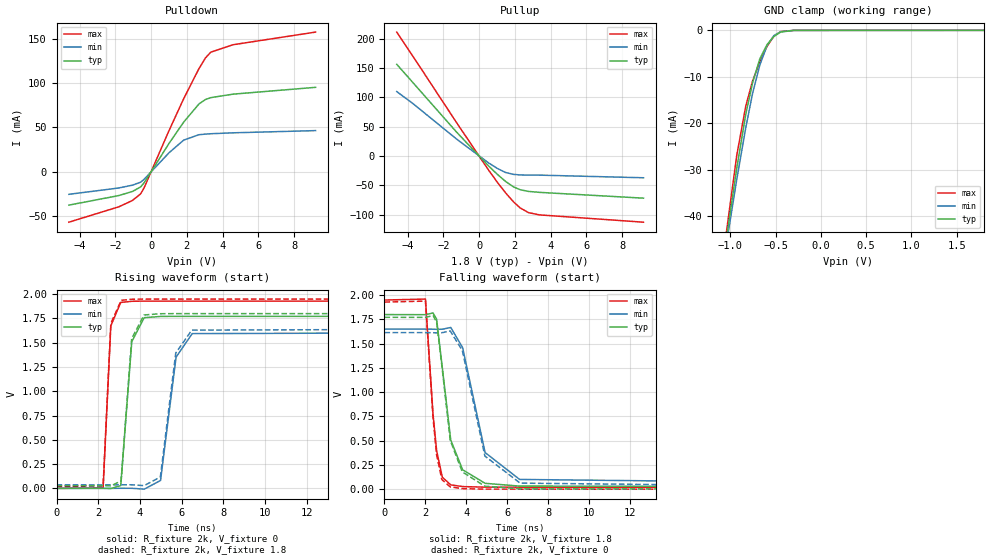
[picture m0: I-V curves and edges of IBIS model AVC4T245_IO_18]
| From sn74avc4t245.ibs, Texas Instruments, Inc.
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[Model]   AVC4T245_IO_18
Model_type  I/O
Vinl=0.5775
Vinh=1.2675
Enable   Active-Low
Vref =   0
Rref =   2000
Cref =   15p
Vmeas =   0.9
| variable   typ   min   max
C_comp   5.14pF   4.46pF   5.82pF
| C_pullup   4.67pF   3.49pF   6.82pF
| C_pulldown   4.57pF   4.04pF   4.94pF
| C_tri-state   5.14pF   4.46pF   5.82pF
[Temperature Range]   40   100   -40
| Ambient temperature   25   85   -40
[Voltage range]   1.8   1.65   1.95
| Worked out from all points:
|   slope of the pulldown table from 0 to 0.27 V, typ, clamps not added: 30.8 ohm
|   slope of the pullup table from 0 to 0.27 V, typ, clamps not added: 31.4 ohm
|   GND clamp passes 1 mA (typ) near -0.50 V on its own axis
|   rising waveform, R_fixture 2k, V_fixture 0: 20-80 % time 305ps typ, 478ps min, 201ps max; typ from 0 V to 1.77 V
|   falling waveform, R_fixture 2k, V_fixture 1.8: 20-80 % time 644ps typ, 986ps min, 377ps max; typ from 1.8 V to 0.027 V
|   rising waveform, R_fixture 2k, V_fixture 1.8: 20-80 % time 303ps typ, 469ps min, 199ps max; typ from 0.027 V to 1.8 V
|   falling waveform, R_fixture 2k, V_fixture 0: 20-80 % time 646ps typ, 986ps min, 364ps max; typ from 1.77 V to 0 V
[GND Clamp]
| AVC4T245_IO_18
|   Voltage   I(typ)   I(min)   I(max)
-4.6V     -600.6mA   -549.4mA   -665.2mA
-1.1V     -52.36mA   -52.84mA   -51.77mA
-1.075V   -48.9mA    -49.7mA    -47.87mA
-930mV    -29.64mA   -32.08mA   -26.89mA
-830mV    -18.03mA   -20.88mA   -16.26mA
-755mV    -11.28mA   -13.55mA   -10.89mA
-675mV    -6.13mA    -7.456mA   -6.788mA
-595mV    -3.055mA   -3.264mA   -3.436mA
-520mV    -1.318mA   -1.135mA   -1.268mA
-445mV    -373.4uA   -312.3uA   -266.4uA
-300mV    -9.535uA   -12.1uA    -2.471uA
1.8V      917.3pA    144.8nA    105pA
[Pulldown]
| AVC4T245_IO_18
|   Voltage   I(typ)   I(min)   I(max)
-4.6V     -37.94mA   -25.73mA   -57.23mA
-1.805V   -27.11mA   -18.54mA   -39.83mA
-1.045V   -22.5mA    -15.36mA   -32.7mA
-590mV    -17.44mA   -12.06mA   -25.35mA
-395mV    -12.81mA   -8.801mA   -18.52mA
1.005V    31.93mA    21.31mA    46.48mA
1.825V    55.97mA    35.61mA    82.46mA
2.68V     76.51mA    41.68mA    116.5mA
3.045V    81.48mA    42.38mA    128.6mA
3.34V     83.6mA     42.77mA    135mA
4.58V     87.53mA    43.81mA    143.4mA
9.2V      95.24mA    46.32mA    157.7mA
[Pullup]
| AVC4T245_IO_18
|   Voltage   I(typ)   I(min)   I(max)
-4.6V     156.3mA    109.9mA    211.2mA
-3.695V   125.1mA    89.45mA    169.9mA
-1.245V   40.55mA    28.8mA     56.51mA
535mV     -16.77mA   -11.6mA    -23.84mA
1.065V    -32.16mA   -21.66mA   -46.14mA
1.49V     -43.16mA   -27.88mA   -62.67mA
1.925V    -52.28mA   -31.05mA   -77.72mA
2.305V    -57.27mA   -32.09mA   -88.3mA
2.77V     -60.1mA    -32.26mA   -96.25mA
3.4V      -61.74mA   -32.39mA   -100.1mA
9.2V      -71.58mA   -36.85mA   -112.5mA
[Ramp]
| AVC4T245_IO_18
| variable   typ   min   max
dV/dt_r   1.08/3.10E-10   0.98/4.92E-10   1.17/2.10E-10
dV/dt_f   1.08/6.51E-10   0.98/9.92E-10   1.17/3.80E-10
R_load = 2k
[Rising Waveform]
| AVC4T245_IO_18
R_fixture =   2k
C_fixture =   0
L_fixture =   0
V_fixture =   0
V_fixture_min = 0
V_fixture_max = 0
|   Time   V(typ)   V(min)   V(max)
0s        21.36nV    98.35nV    643.8pV
2.235ns   939uV      -63.18uV   3.952mV
2.605ns   -1.623mV   -102.8uV   1.674V
3.08ns    28.68mV    976.3uV    1.915V
3.61ns    1.511V     850.9uV    1.927V
4.205ns   1.758V     -8.24mV    1.929V
4.99ns    1.771V     81.14mV    1.929V
5.735ns   1.772V     1.352V     1.929V
6.51ns    1.772V     1.594V     1.929V
34.99ns   1.772V     1.614V     1.929V
[Falling Waveform]
| AVC4T245_IO_18
R_fixture =   2k
C_fixture =   0
L_fixture =   0
V_fixture =   1.8
V_fixture_min = 1.65
V_fixture_max = 1.95
|   Time   V(typ)   V(min)   V(max)
0s        1.8V       1.65V      1.95V
2ns       1.799V     1.65V      1.96V
2.37ns    1.817V     1.649V     773.9mV
2.545ns   1.752V     1.648V     397.5mV
2.825ns   1.249V     1.649V     122.4mV
3.235ns   505.1mV    1.667V     44.21mV
3.815ns   199.7mV    1.459V     26.65mV
4.91ns    60.3mV     377.5mV    20.79mV
6.595ns   31.42mV    100.3mV    20.47mV
34.99ns   27.15mV    36.2mV     20.45mV
[Rising Waveform]
| AVC4T245_IO_18
R_fixture =   2k
C_fixture =   0
L_fixture =   0
V_fixture =   1.8
V_fixture_min = 1.65
V_fixture_max = 1.95
|   Time   V(typ)   V(min)   V(max)
0s        27.15mV    36.2mV     20.45mV
2.235ns   28.08mV    36.15mV    24.79mV
2.605ns   25.45mV    36.12mV    1.699V
3.1ns     77.01mV    37.21mV    1.937V
3.605ns   1.542V     36.93mV    1.948V
4.2ns     1.786V     28.08mV    1.95V
4.98ns    1.799V     116.2mV    1.95V
5.72ns    1.8V       1.394V     1.95V
6.49ns    1.8V       1.63V      1.95V
34.99ns   1.8V       1.65V      1.95V
[Falling Waveform]
| AVC4T245_IO_18
R_fixture =   2k
C_fixture =   0
L_fixture =   0
V_fixture =   0
V_fixture_min = 0
V_fixture_max = 0
|   Time   V(typ)   V(min)   V(max)
0s        1.772V     1.614V     1.929V
2ns       1.771V     1.614V     1.939V
2.375ns   1.79V      1.613V     723.7mV
2.545ns   1.723V     1.612V     354.3mV
2.8ns     1.276V     1.613V     98.99mV
3.21ns    503.2mV    1.631V     22.91mV
3.8ns     177.2mV    1.429V     5.502mV
4.9ns     30.64mV    341.2mV    292.6uV
6.62ns    3.645mV    62.11mV    18.86uV
34.99ns   89.82nV    420.4nV    159.5nV
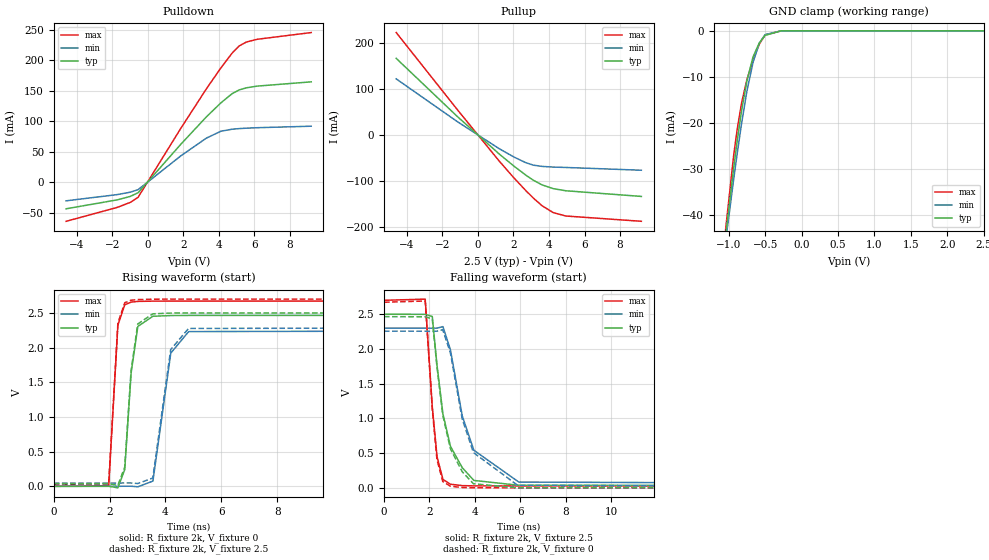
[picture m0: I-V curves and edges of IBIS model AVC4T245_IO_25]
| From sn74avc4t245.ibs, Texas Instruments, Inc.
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[Model]   AVC4T245_IO_25
Model_type  I/O
Vinl=0.7
Vinh=1.6
Enable   Active-Low
Vref =   0
Rref =   2000
Cref =   15p
Vmeas =   1.25
| variable   typ   min   max
C_comp   4.97pF   4.22pF   5.78pF
| C_pullup   4.14pF   3.18pF   5.58pF
| C_pulldown   4.27pF   3.78pF   4.75pF
| C_tri-state   4.97pF   4.22pF   5.78pF
[Temperature Range]   40   100   -40
| Ambient temperature   25   85   -40
[Voltage range]   2.5   2.3   2.7
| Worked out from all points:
|   slope of the pulldown table from 0 to 0.375 V, typ, clamps not added: 29.4 ohm
|   slope of the pullup table from 0 to 0.375 V, typ, clamps not added: 28.8 ohm
|   GND clamp passes 1 mA (typ) near -0.50 V on its own axis
|   rising waveform, R_fixture 2k, V_fixture 0: 20-80 % time 249ps typ, 382ps min, 174ps max; typ from 0 V to 2.46 V
|   falling waveform, R_fixture 2k, V_fixture 2.5: 20-80 % time 729ps typ, 1.03ns min, 343ps max; typ from 2.5 V to 0.036 V
|   rising waveform, R_fixture 2k, V_fixture 2.5: 20-80 % time 247ps typ, 378ps min, 173ps max; typ from 0.036 V to 2.5 V
|   falling waveform, R_fixture 2k, V_fixture 0: 20-80 % time 723ps typ, 1.03ns min, 335ps max; typ from 2.46 V to 0 V
[GND Clamp]
| AVC4T245_IO_25
|   Voltage   I(typ)   I(min)   I(max)
-4.6V     -600.6mA   -549.4mA   -665.2mA
-1.105V   -53.06mA   -53.47mA   -52.55mA
-1.08V    -49.59mA   -50.32mA   -48.65mA
-930mV    -29.64mA   -32.08mA   -26.89mA
-880mV    -23.56mA   -26.34mA   -21.06mA
-825mV    -17.52mA   -20.36mA   -15.83mA
-750mV    -10.9mA    -13.11mA   -10.61mA
-665mV    -5.638mA   -6.831mA   -6.326mA
-580mV    -2.642mA   -2.696mA   -2.914mA
-500mV    -988.4uA   -825.2uA   -890.7uA
-280mV    -5.263uA   -7.284uA   -1.131uA
2.5V      1.211nA    546.5nA    158.6pA
[Pulldown]
| AVC4T245_IO_25
|   Voltage   I(typ)   I(min)   I(max)
-4.6V     -43.76mA   -30.71mA   -64.27mA
-1.715V   -29.08mA   -20.46mA   -41.45mA
-985mV    -23.44mA   -16.53mA   -33.24mA
-545mV    -17.41mA   -12.35mA   -24.86mA
1.85V     61.76mA    42.85mA    87.78mA
3.295V    106.9mA    72.08mA    152.8mA
4.12V     130.1mA    83.49mA    187.5mA
4.755V    145.2mA    86.77mA    211.8mA
5.15V     151.2mA    87.75mA    223.4mA
5.55V     154.6mA    88.43mA    229.7mA
6.155V    157.4mA    89.2mA     234.2mA
9.2V      164.4mA    91.67mA    245.2mA
[Pullup]
| AVC4T245_IO_25
|   Voltage   I(typ)   I(min)   I(max)
-4.6V     167.2mA    122.6mA    223.3mA
-1.155V   40.55mA    29.45mA    55.44mA
1.195V    -40.71mA   -29.18mA   -56.05mA
2.025V    -67.14mA   -47.36mA   -92.77mA
2.695V    -86.73mA   -59.71mA   -120.4mA
3.12V     -97.9mA    -65.07mA   -136.7mA
3.615V    -108.1mA   -67.81mA   -153.5mA
4.245V    -116.2mA   -69.29mA   -168.4mA
4.95V     -120.8mA   -70.1mA    -175.7mA
9.2V      -133.1mA   -76.13mA   -187.2mA
[Ramp]
| AVC4T245_IO_25
| variable   typ   min   max
dV/dt_r   1.50/2.56E-10   1.37/3.91E-10   1.62/1.82E-10
dV/dt_f   1.49/7.31E-10   1.37/1.04E-09   1.61/3.45E-10
R_load = 2k
[Rising Waveform]
| AVC4T245_IO_25
R_fixture =   2k
C_fixture =   0
L_fixture =   0
V_fixture =   0
V_fixture_min = 0
V_fixture_max = 0
|   Time   V(typ)   V(min)   V(max)
0s        27.72nV    106.5nV    1.06nV
1.965ns   1.484mV    -36.8uV    6.573mV
2.295ns   -22.18mV   23.98nV    2.324V
2.54ns    241.3mV    1.689mV    2.618V
2.77ns    1.638V     1.446mV    2.657V
3.01ns    2.307V     -7.124mV   2.667V
3.55ns    2.453V     75.71mV    2.671V
4.19ns    2.463V     1.922V     2.672V
4.83ns    2.465V     2.232V     2.672V
34.99ns   2.465V     2.256V     2.672V
[Falling Waveform]
| AVC4T245_IO_25
R_fixture =   2k
C_fixture =   0
L_fixture =   0
V_fixture =   2.5
V_fixture_min = 2.3
V_fixture_max = 2.7
|   Time   V(typ)   V(min)   V(max)
0s        2.5V       2.3V       2.7V
1.815ns   2.498V     2.3V       2.717V
2.125ns   2.467V     2.298V     1.17V
2.335ns   1.76V      2.3V       449.4mV
2.595ns   1.064V     2.321V     120.7mV
2.925ns   598mV      1.985V     52.14mV
3.445ns   290mV      1.034V     32.45mV
3.955ns   107mV      541.3mV    28.62mV
5.93ns    36.97mV    83.48mV    27.64mV
34.99ns   36.05mV    46.86mV    27.62mV
[Rising Waveform]
| AVC4T245_IO_25
R_fixture =   2k
C_fixture =   0
L_fixture =   0
V_fixture =   2.5
V_fixture_min = 2.3
V_fixture_max = 2.7
|   Time   V(typ)   V(min)   V(max)
0s        36.05mV    46.86mV    27.62mV
1.965ns   37.54mV    46.82mV    34.28mV
2.295ns   13.86mV    46.86mV    2.355V
2.54ns    279.4mV    48.54mV    2.648V
2.765ns   1.657V     48.31mV    2.684V
3.005ns   2.341V     39.89mV    2.694V
3.545ns   2.488V     119.6mV    2.699V
4.185ns   2.499V     1.972V     2.7V
4.825ns   2.5V       2.277V     2.7V
34.99ns   2.5V       2.3V       2.7V
[Falling Waveform]
| AVC4T245_IO_25
R_fixture =   2k
C_fixture =   0
L_fixture =   0
V_fixture =   0
V_fixture_min = 0
V_fixture_max = 0
|   Time   V(typ)   V(min)   V(max)
0s        2.465V     2.256V     2.672V
1.815ns   2.463V     2.255V     2.69V
2.125ns   2.432V     2.253V     1.133V
2.33ns    1.747V     2.256V     410.5mV
2.585ns   1.051V     2.277V     91.9mV
2.92ns    564.3mV    1.947V     23.48mV
3.44ns    233.8mV    993.9mV    4.515mV
3.935ns   59.05mV    507.7mV    976.4uV
5.88ns    813.4uV    36.57mV    20.32uV
34.99ns   384.5nV    341.4nV    230.5nV
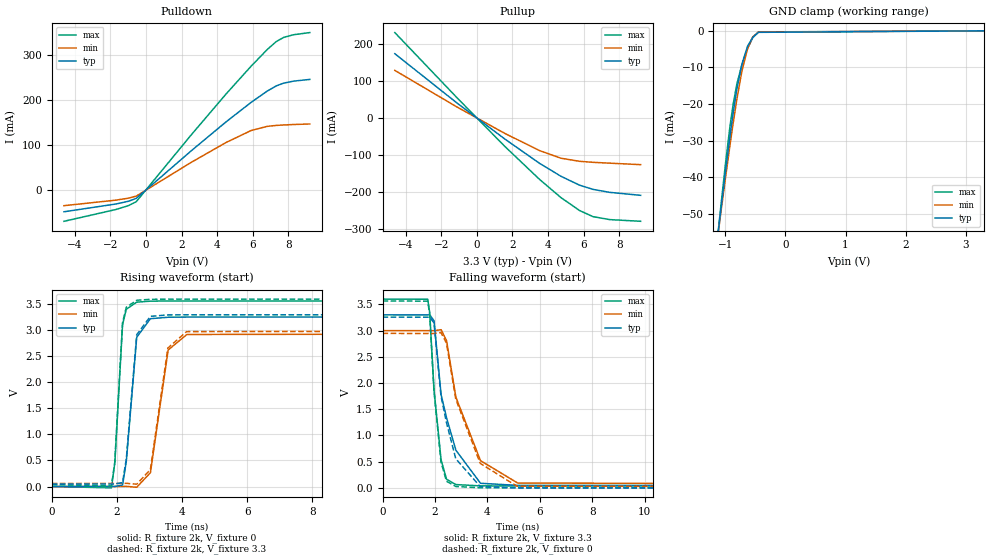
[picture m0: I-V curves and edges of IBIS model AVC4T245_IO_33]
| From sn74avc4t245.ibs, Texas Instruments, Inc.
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[Model]   AVC4T245_IO_33
Model_type  I/O
Vinl=0.8
Vinh=2.0
Enable   Active-Low
Vref =   0
Rref =   2000
Cref =   15p
Vmeas =   1.65
| variable   typ   min   max
C_comp   4.82pF   4.03pF   5.73pF
| C_pullup   3.88pF   2.96pF   5.19pF
| C_pulldown   4.08pF   3.59pF   4.69pF
| C_tri-state   4.82pF   4.03pF   5.73pF
[Temperature Range]   40   100   -40
| Ambient temperature   25   85   -40
[Voltage range]   3.3   3   3.6
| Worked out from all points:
|   slope of the pulldown table from 0 to 0.495 V, typ, clamps not added: 28.7 ohm
|   slope of the pullup table from 0 to 0.495 V, typ, clamps not added: 27.4 ohm
|   GND clamp passes 1 mA (typ) near -0.50 V on its own axis
|   rising waveform, R_fixture 2k, V_fixture 0: 20-80 % time 231ps typ, 351ps min, 169ps max; typ from 0 V to 3.26 V
|   falling waveform, R_fixture 2k, V_fixture 3.3: 20-80 % time 750ps typ, 1ns min, 330ps max; typ from 3.3 V to 0.046 V
|   rising waveform, R_fixture 2k, V_fixture 3.3: 20-80 % time 230ps typ, 352ps min, 169ps max; typ from 0.046 V to 3.3 V
|   falling waveform, R_fixture 2k, V_fixture 0: 20-80 % time 665ps typ, 1ns min, 326ps max; typ from 3.26 V to 0 V
[GND Clamp]
| AVC4T245_IO_33
|   Voltage   I(typ)   I(min)   I(max)
-4.6V     -600.6mA   -549.4mA   -665.2mA
-1.12V    -55.16mA   -55.36mA   -54.92mA
-1.09V    -50.97mA   -51.58mA   -50.2mA
-1V       -38.73mA   -40.44mA   -36.55mA
-920mV    -28.39mA   -30.91mA   -25.64mA
-870mV    -22.4mA    -25.22mA   -20.03mA
-810mV    -16.03mA   -18.81mA   -14.6mA
-725mV    -9.111mA   -11.03mA   -9.257mA
-630mV    -4.182mA   -4.867mA   -4.797mA
-545mV    -1.809mA   -1.655mA   -1.862mA
-450mV    -412.7uA   -343.4uA   -301.7uA
3.3V      1.644nA    2.398uA    241.4pA
[Pulldown]
| AVC4T245_IO_33
|   Voltage   I(typ)   I(min)   I(max)
-4.6V     -47.48mA   -33.99mA   -68.59mA
-1.685V   -30.29mA   -21.73mA   -42.48mA
-980mV    -24.2mA    -17.36mA   -33.89mA
-545mV    -17.86mA   -12.84mA   -25.24mA
2.54V     87.35mA    61.85mA    122.6mA
4.5V      151.6mA    105.9mA    213.3mA
5.905V    194.7mA    132.4mA    274.8mA
6.805V    219.6mA    141.6mA    311.5mA
7.315V    231.2mA    143.7mA    329.3mA
7.73V     237.3mA    144.7mA    338.5mA
8.275V    241.7mA    145.7mA    344.4mA
9.2V      245.6mA    146.9mA    349.3mA
[Pullup]
| AVC4T245_IO_33
|   Voltage   I(typ)   I(min)   I(max)
-4.6V     174.2mA    129.1mA    231.4mA
-1.105V   40.58mA    29.86mA    54.82mA
1.575V    -56.66mA   -41.45mA   -76.65mA
3.53V     -122.6mA   -88.07mA   -166.1mA
4.72V     -157.3mA   -108.5mA   -214.9mA
5.77V     -181.5mA   -117mA     -250.1mA
6.525V    -192.9mA   -119.7mA   -266.7mA
7.465V    -201mA     -122mA     -274.7mA
9.2V      -209mA     -126mA     -279.3mA
[Ramp]
| AVC4T245_IO_33
| variable   typ   min   max
dV/dt_r   1.97/2.35E-10   1.79/3.60E-10   2.16/1.73E-10
dV/dt_f   1.95/7.51E-10   1.78/1.00E-09   2.14/3.32E-10
R_load = 2k
[Rising Waveform]
| AVC4T245_IO_33
R_fixture =   2k
C_fixture =   0
L_fixture =   0
V_fixture =   0
V_fixture_min = 0
V_fixture_max = 0
|   Time   V(typ)   V(min)   V(max)
0s        38nV       120.5nV    1.922nV
1.835ns   1.597mV    -34.6uV    -26.08mV
1.94ns    159uV      5.411uV    470.6mV
2.175ns   29.45mV    946.8uV    3.111V
2.29ns    480.5mV    2.447mV    3.406V
2.61ns    2.867V     -14.56mV   3.542V
3.03ns    3.224V     264.7mV    3.561V
3.575ns   3.252V     2.623V     3.564V
4.15ns    3.255V     2.921V     3.564V
34.99ns   3.256V     2.946V     3.564V
[Falling Waveform]
| AVC4T245_IO_33
R_fixture =   2k
C_fixture =   0
L_fixture =   0
V_fixture =   3.3
V_fixture_min = 3
V_fixture_max = 3.6
|   Time   V(typ)   V(min)   V(max)
0s        3.3V       3V         3.6V
1.725ns   3.299V     2.999V     3.598V
1.8ns     3.302V     2.999V     3.341V
1.965ns   3.188V     2.998V     1.869V
2.235ns   1.779V     3.017V     534.7mV
2.445ns   1.334V     2.806V     163.5mV
2.8ns     718.1mV    1.729V     62.88mV
3.74ns    87.28mV    518.2mV    37.4mV
5.16ns    47.49mV    91.81mV    36.37mV
34.99ns   46.48mV    58.85mV    36.33mV
[Rising Waveform]
| AVC4T245_IO_33
R_fixture =   2k
C_fixture =   0
L_fixture =   0
V_fixture =   3.3
V_fixture_min = 3
V_fixture_max = 3.6
|   Time   V(typ)   V(min)   V(max)
0s        46.48mV    58.85mV    36.33mV
1.835ns   48.08mV    58.82mV    10.17mV
1.935ns   47.06mV    58.86mV    461.6mV
2.175ns   76.19mV    59.8mV     3.15V
2.29ns    529mV      61.3mV     3.444V
2.61ns    2.916V     44.12mV    3.579V
3.03ns    3.269V     327.1mV    3.596V
3.565ns   3.297V     2.66V      3.599V
4.14ns    3.299V     2.976V     3.6V
34.99ns   3.3V       3V         3.6V
[Falling Waveform]
| AVC4T245_IO_33
R_fixture =   2k
C_fixture =   0
L_fixture =   0
V_fixture =   0
V_fixture_min = 0
V_fixture_max = 0
|   Time   V(typ)   V(min)   V(max)
0s        3.256V     2.946V     3.564V
1.725ns   3.255V     2.945V     3.562V
1.8ns     3.258V     2.944V     3.305V
1.965ns   3.145V     2.943V     1.84V
2.23ns    1.755V     2.963V     496.6mV
2.44ns    1.246V     2.762V     126.7mV
2.795ns   555mV      1.693V     26.33mV
3.73ns    24.57mV    465.9mV    1.073mV
5.125ns   626.8uV    33.08mV    40.03uV
34.99ns   487.8nV    719.1nV    216.1nV
